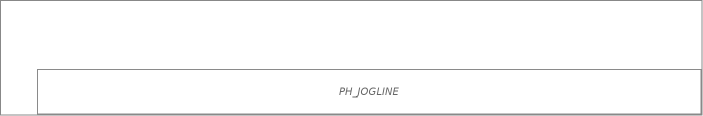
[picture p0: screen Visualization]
VISUALIZATION Visualization  // 703x116
    Frame (37,69 664x45)
        shows PH_JOGLINE(m_Input_Name := MAIN.axis1)
END_VISUALIZATION
